One B-rep face of a CAD part: STEP entity #756.
In plain terms, the planar face has unit normal (1, 0, 0).
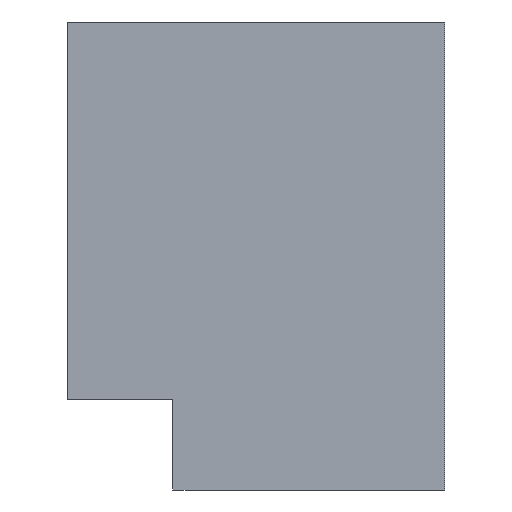
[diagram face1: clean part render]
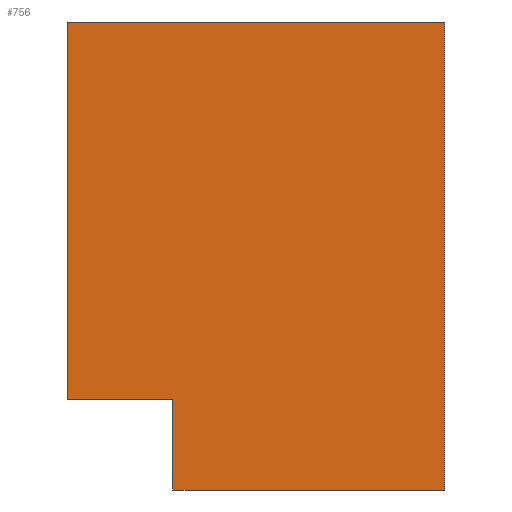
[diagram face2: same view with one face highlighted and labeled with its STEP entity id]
Its self-contained STEP definition (entity closure, numbers rounded to 3 decimals):
#701=CARTESIAN_POINT('Axis2P3D Location',(-50.,0.,0.)) ;
#706=CARTESIAN_POINT('Line Origine',(-50.,5.5,-28.)) ;
#710=CARTESIAN_POINT('Vertex',(-50.,5.5,-31.)) ;
#712=CARTESIAN_POINT('Vertex',(-50.,5.5,-25.)) ;
#715=CARTESIAN_POINT('Line Origine',(-50.,9.,-25.)) ;
#719=CARTESIAN_POINT('Vertex',(-50.,12.5,-25.)) ;
#722=CARTESIAN_POINT('Line Origine',(-50.,12.5,-12.5)) ;
#726=CARTESIAN_POINT('Vertex',(-50.,12.5,0.)) ;
#729=CARTESIAN_POINT('Line Origine',(-50.,0.,0.)) ;
#733=CARTESIAN_POINT('Vertex',(-50.,-12.5,0.)) ;
#736=CARTESIAN_POINT('Line Origine',(-50.,-12.5,-15.5)) ;
#740=CARTESIAN_POINT('Vertex',(-50.,-12.5,-31.)) ;
#743=CARTESIAN_POINT('Line Origine',(-50.,-3.5,-31.)) ;
#702=DIRECTION('Axis2P3D Direction',(1.,0.,0.)) ;
#703=DIRECTION('Axis2P3D XDirection',(0.,1.,0.)) ;
#707=DIRECTION('Vector Direction',(0.,0.,1.)) ;
#716=DIRECTION('Vector Direction',(0.,1.,0.)) ;
#723=DIRECTION('Vector Direction',(0.,0.,1.)) ;
#730=DIRECTION('Vector Direction',(0.,-1.,0.)) ;
#737=DIRECTION('Vector Direction',(0.,0.,-1.)) ;
#744=DIRECTION('Vector Direction',(0.,1.,0.)) ;
#704=AXIS2_PLACEMENT_3D('Plane Axis2P3D',#701,#702,#703) ;
#749=ORIENTED_EDGE('',*,*,#714,.T.) ;
#750=ORIENTED_EDGE('',*,*,#721,.T.) ;
#751=ORIENTED_EDGE('',*,*,#728,.T.) ;
#752=ORIENTED_EDGE('',*,*,#735,.T.) ;
#753=ORIENTED_EDGE('',*,*,#742,.T.) ;
#754=ORIENTED_EDGE('',*,*,#747,.T.) ;
#708=VECTOR('Line Direction',#707,1.) ;
#717=VECTOR('Line Direction',#716,1.) ;
#724=VECTOR('Line Direction',#723,1.) ;
#731=VECTOR('Line Direction',#730,1.) ;
#738=VECTOR('Line Direction',#737,1.) ;
#745=VECTOR('Line Direction',#744,1.) ;
#756=ADVANCED_FACE('MANIFOLD_SOLID_BREP #3688',(#755),#705,.T.) ;
#714=EDGE_CURVE('',#711,#713,#709,.T.) ;
#721=EDGE_CURVE('',#713,#720,#718,.T.) ;
#728=EDGE_CURVE('',#720,#727,#725,.T.) ;
#735=EDGE_CURVE('',#727,#734,#732,.T.) ;
#742=EDGE_CURVE('',#734,#741,#739,.T.) ;
#747=EDGE_CURVE('',#741,#711,#746,.T.) ;
#748=EDGE_LOOP('',(#749,#750,#751,#752,#753,#754)) ;
#755=FACE_OUTER_BOUND('',#748,.T.) ;
#709=LINE('Line',#706,#708) ;
#718=LINE('Line',#715,#717) ;
#725=LINE('Line',#722,#724) ;
#732=LINE('Line',#729,#731) ;
#739=LINE('Line',#736,#738) ;
#746=LINE('Line',#743,#745) ;
#705=PLANE('Plane',#704) ;
#711=VERTEX_POINT('',#710) ;
#713=VERTEX_POINT('',#712) ;
#720=VERTEX_POINT('',#719) ;
#727=VERTEX_POINT('',#726) ;
#734=VERTEX_POINT('',#733) ;
#741=VERTEX_POINT('',#740) ;
